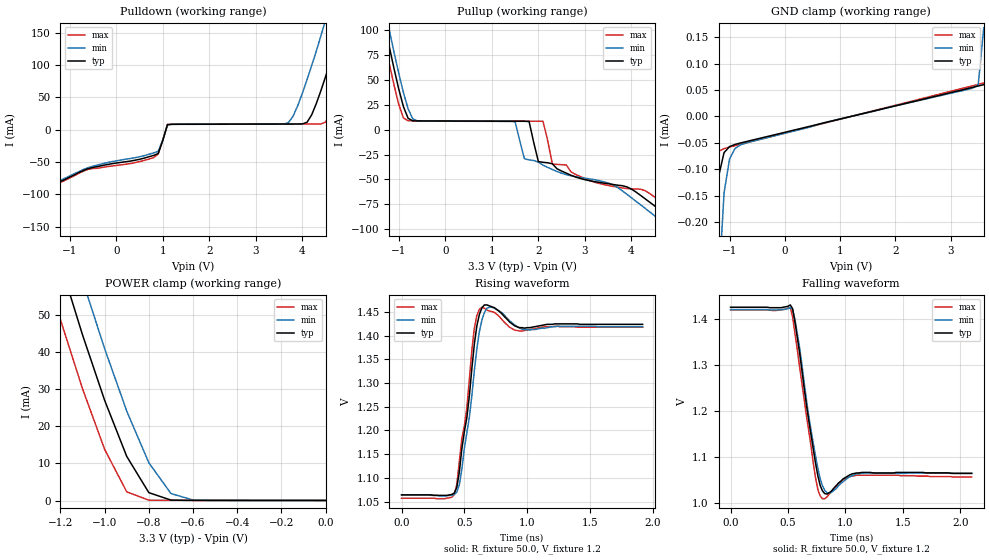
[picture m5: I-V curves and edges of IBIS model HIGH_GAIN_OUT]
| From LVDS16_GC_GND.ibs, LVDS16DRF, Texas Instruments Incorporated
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|   Driver Output Model
[Model]   HIGH_GAIN_OUT
Model_type   3-state
| Signals   Y, Z
Vmeas = 1.2V   |Reference voltage for timing measurements
Cref = 1pF   |Timing specification test load capacitance value
Rref = 50   |Note: 50 Ohm load; single ended configuration
Vref = 1.20V   |Timing specification test load voltage
|Note: 50 Ohm load; single ended configuration
| variable   typ   min   max
C_comp   1.23pF   1.21pF   1.3pF
|   typ   min   max
[Temperature Range]   25.0   -40.0   85.0
[Voltage range]   3.3V   3.0V   3.6V
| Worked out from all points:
|   slope of the pulldown table from 0 to 0.495 V, typ, clamps not added: 86.5 ohm
|   slope of the pullup table from 0 to 0.495 V, typ, clamps not added: 7.12 kohm
|   GND clamp passes 1 mA (typ) near -1.45 V on its own axis
|   POWER clamp passes 1 mA (typ) near -0.74 V on its own axis
|   rising waveform, R_fixture 50.0, V_fixture 1.2: 20-80 % time 98.3ps typ, 101ps min, 94.2ps max; typ from 1.06 V to 1.42 V
|   falling waveform, R_fixture 50.0, V_fixture 1.2: 20-80 % time 123ps typ, 123ps min, 124ps max; typ from 1.43 V to 1.06 V
[Pulldown]
|Voltage I(typ)   I(min)   I(max)
-3.3V     -161mA     -162mA     -161mA
-700mV    -62.9mA    -61.4mA    -63.9mA
800mV     -39.8mA    -35.9mA    -43.3mA
900mV     -37mA      -33.5mA    -37.6mA
1.1V      7.74mA     7.43mA     8.28mA
3.7V      8.79mA     11mA       8.85mA
4.1V      11.5mA     77.4mA     8.9mA
4.4V      60.9mA     146mA      8.99mA
4.5V      82.6mA     170mA      11.8mA
4.8V      152mA      245mA      65.5mA
5.2V      253mA      349mA      159mA
6.6V      642mA      751mA      537mA
[Pullup]
|Voltage   I(typ)   I(min)   I(max)
| Note that the[Pullup]voltage table is referenced to Vcc
| and is calculated using Vtable=Vcc - Vmeasured.
-3.3V     642mA      661mA      625mA
-1.4V     128mA      146mA      111mA
-1.3V     105mA      122mA      87.8mA
-1V       40.7mA     56.5mA     25.3mA
-800mV    11.5mA     21mA       8.99mA
1.5V      8.51mA     8.03mA     8.63mA
1.8V      8.23mA     -30.4mA    8.59mA
2.1V      -32.8mA    -35.7mA    8.5mA
2.3V      -34.2mA    -40mA      -34.5mA
3.6V      -55.1mA    -55.4mA    -57mA
4.9V      -91.1mA    -102mA     -81.4mA
6.6V      -161mA     -177mA     -146mA
[GND_clamp]
|Voltage   I(typ)   I(min)   I(max)
-3.6V     -79.4mA    -88.2mA    -41.5mA
-1.4V     -676uA     -1.36mA    -215uA
-1.3V     -277uA     -722uA     -90.9uA
-1.2V     -114uA     -328uA     -66.4uA
-1.1V     -68.6uA    -145uA     -61uA
-1V       -57.2uA    -80.4uA    -58.1uA
-900mV    -53.1uA    -60.6uA    -55.5uA
-700mV    -47.8uA    -50.3uA    -50.2uA
700mV     -12.5uA    -12.2uA    -13.2uA
3.4V      55.1uA     53.5uA     58uA
3.5V      57.6uA     60.2uA     60.7uA
3.6V      60.1uA     168uA      63.3uA
[Power_clamp]
| Note that the[POWER_clamp]voltage table is referenced to Vcc
| and is calculated using Vtable=Vcc - Vmeasured.
|Voltage   I(typ)   I(min)   I(max)
-3.3V     622mA      646mA      598mA
-1.3V     84.5mA     100mA      69mA
-1.2V     63.8mA     79.2mA     48.7mA
-1.1V     44.6mA     59.3mA     30.1mA
-1V       27mA       40.9mA     13.8mA
-900mV    11.9mA     24.1mA     2.37mA
-800mV    2.15mA     10.2mA     120uA
-700mV    145uA      1.91mA     82.1uA
-600mV    69.2uA     168uA      79.2uA
0V        52.6uA     43.8uA     63.3uA
[Ramp]
|   typ   min   max
dV/dt_r   0.215/82ps   0.213/100ps   0.217/90ps
dV/dt_f   0.217/100ps   0.214/120ps   0.218/120ps
R_load = 50ohm |Note: The measurement is on a single-ended configuration
|   with 100ohm line-to-line.
[Rising Waveform]
R_fixture = 50.0
V_fixture = 1.2
C_fixture = 0p
L_fixture = 0n
|   V(typ)  V(min)  V(max)
0s        1.064V     1.064V     1.057V
420ps     1.068V     1.065V     1.065V
440ps     1.08V      1.07V      1.086V
460ps     1.112V     1.085V     1.134V
520ps     1.227V     1.195V     1.248V
580ps     1.383V     1.327V     1.416V
640ps     1.459V     1.433V     1.46V
720ps     1.461V     1.46V      1.451V
940ps     1.417V     1.416V     1.41V
1.92ns    1.424V     1.419V     1.418V
[Falling Waveform]
R_fixture = 50.0
V_fixture = 1.2
C_fixture = 0p
L_fixture = 0n
|   V(typ)  V(min)  V(max)
0s        1.425V     1.42V      1.419V
520ps     1.43V      1.424V     1.424V
560ps     1.394V     1.399V     1.369V
680ps     1.18V      1.19V      1.158V
740ps     1.086V     1.101V     1.054V
800ps     1.026V     1.037V     1.009V
860ps     1.022V     1.021V     1.019V
980ps     1.052V     1.046V     1.05V
1.1ns     1.065V     1.063V     1.06V
2.1ns     1.064V     1.064V     1.056V
